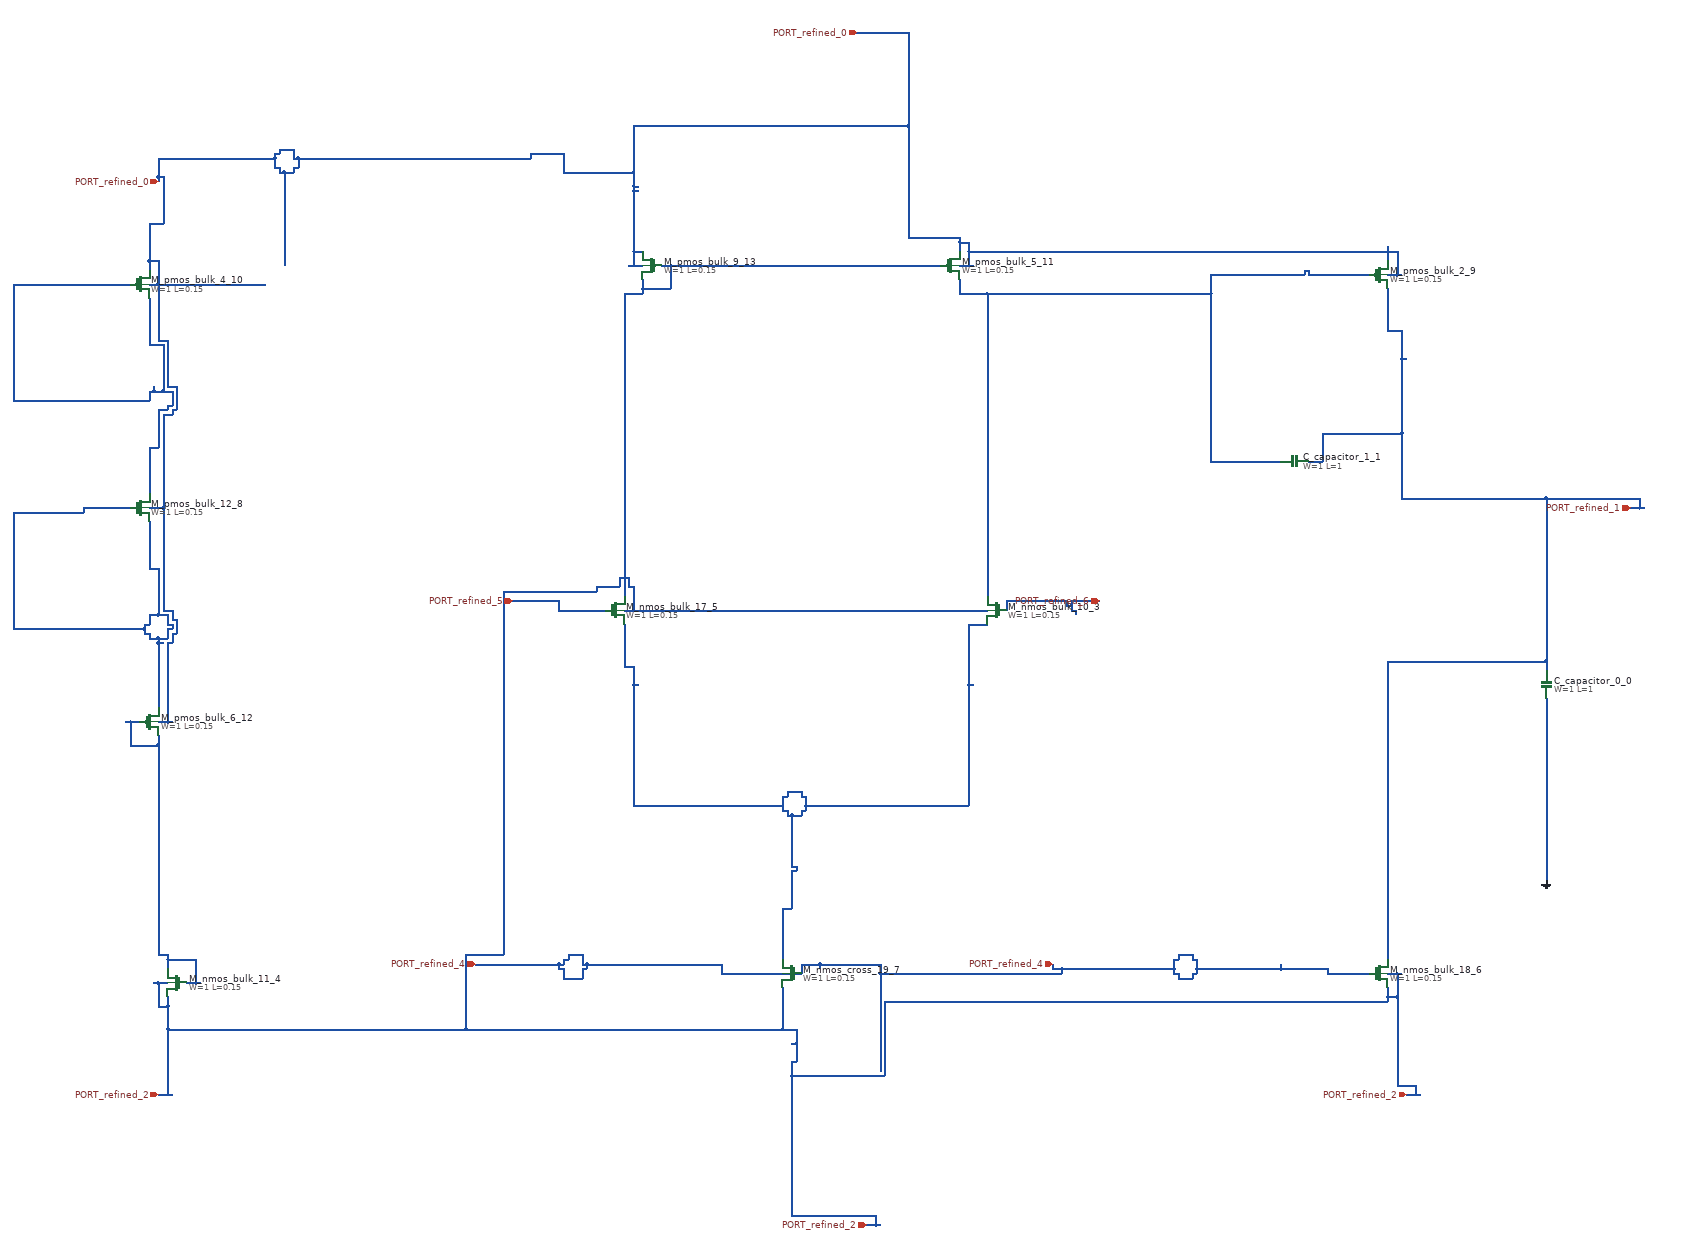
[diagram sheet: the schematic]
v {xschem version=3.4.8 file_version=1.2}
G {}
K {}
V {}
S {}
E {}
C {sky130_fd_pr/cap_mim_m3_1.sym} 3380 1500 2 0 {name="C_capacitor_0_0" model=cap_mim_m3_1 W=1 L=1 MF=1 spiceprefix=X}
C {sky130_fd_pr/cap_mim_m3_1.sym} 2840 1020 1 0 {name="C_capacitor_1_1" model=cap_mim_m3_1 W=1 L=1 MF=1 spiceprefix=X}
C {devices/gnd.sym} 3380 1920 0 0 {name="l_gnd_14_2" lab="GND"}
C {sky130_fd_pr/nfet_01v8.sym} 2200 1340 0 1 {name="M_nmos_bulk_10_3"
W=1
L=0.15
nf=1 
mult=1
ad="expr('int((@nf + 1)/2) * @W / @nf * 0.29')"
pd="expr('2*int((@nf + 1)/2) * (@W / @nf + 0.29)')"
as="expr('int((@nf + 2)/2) * @W / @nf * 0.29')"
ps="expr('2*int((@nf + 2)/2) * (@W / @nf + 0.29)')"
nrd="expr('0.29 / @W ')" nrs="expr('0.29 / @W ')"
sa=0 sb=0 sd=0
model=nfet_01v8
spiceprefix=X
}
C {sky130_fd_pr/nfet_01v8.sym} 440 2140 0 1 {name="M_nmos_bulk_11_4"
W=1
L=0.15
nf=1 
mult=1
ad="expr('int((@nf + 1)/2) * @W / @nf * 0.29')"
pd="expr('2*int((@nf + 1)/2) * (@W / @nf + 0.29)')"
as="expr('int((@nf + 2)/2) * @W / @nf * 0.29')"
ps="expr('2*int((@nf + 2)/2) * (@W / @nf + 0.29)')"
nrd="expr('0.29 / @W ')" nrs="expr('0.29 / @W ')"
sa=0 sb=0 sd=0
model=nfet_01v8
spiceprefix=X
}
C {sky130_fd_pr/nfet_01v8.sym} 1380 1340 0 0 {name="M_nmos_bulk_17_5"
W=1
L=0.15
nf=1 
mult=1
ad="expr('int((@nf + 1)/2) * @W / @nf * 0.29')"
pd="expr('2*int((@nf + 1)/2) * (@W / @nf + 0.29)')"
as="expr('int((@nf + 2)/2) * @W / @nf * 0.29')"
ps="expr('2*int((@nf + 2)/2) * (@W / @nf + 0.29)')"
nrd="expr('0.29 / @W ')" nrs="expr('0.29 / @W ')"
sa=0 sb=0 sd=0
model=nfet_01v8
spiceprefix=X
}
C {sky130_fd_pr/nfet_01v8.sym} 3020 2120 0 0 {name="M_nmos_bulk_18_6"
W=1
L=0.15
nf=1 
mult=1
ad="expr('int((@nf + 1)/2) * @W / @nf * 0.29')"
pd="expr('2*int((@nf + 1)/2) * (@W / @nf + 0.29)')"
as="expr('int((@nf + 2)/2) * @W / @nf * 0.29')"
ps="expr('2*int((@nf + 2)/2) * (@W / @nf + 0.29)')"
nrd="expr('0.29 / @W ')" nrs="expr('0.29 / @W ')"
sa=0 sb=0 sd=0
model=nfet_01v8
spiceprefix=X
}
C {sky130_fd_pr/nfet3_01v8.sym} 1760 2120 0 1 {name="M_nmos_cross_19_7"
W=1
L=0.15
body=GND
nf=1
mult=1
ad="expr('int((@nf + 1)/2) * @W / @nf * 0.29')"
pd="expr('2*int((@nf + 1)/2) * (@W / @nf + 0.29)')"
as="expr('int((@nf + 2)/2) * @W / @nf * 0.29')"
ps="expr('2*int((@nf + 2)/2) * (@W / @nf + 0.29)')"
nrd="expr('0.29 / @W ')" nrs="expr('0.29 / @W ')"
sa=0 sb=0 sd=0
model=nfet_01v8
spiceprefix=X
}
C {sky130_fd_pr/pfet_01v8.sym} 360 1120 0 0 {name="M_pmos_bulk_12_8"
W=1
L=0.15
nf=1
mult=1
ad="expr('int((@nf + 1)/2) * @W / @nf * 0.29')"
pd="expr('2*int((@nf + 1)/2) * (@W / @nf + 0.29)')"
as="expr('int((@nf + 2)/2) * @W / @nf * 0.29')"
ps="expr('2*int((@nf + 2)/2) * (@W / @nf + 0.29)')"
nrd="expr('0.29 / @W ')" nrs="expr('0.29 / @W ')"
sa=0 sb=0 sd=0
model=pfet_01v8
spiceprefix=X
}
C {sky130_fd_pr/pfet_01v8.sym} 3020 620 0 0 {name="M_pmos_bulk_2_9"
W=1
L=0.15
nf=1
mult=1
ad="expr('int((@nf + 1)/2) * @W / @nf * 0.29')"
pd="expr('2*int((@nf + 1)/2) * (@W / @nf + 0.29)')"
as="expr('int((@nf + 2)/2) * @W / @nf * 0.29')"
ps="expr('2*int((@nf + 2)/2) * (@W / @nf + 0.29)')"
nrd="expr('0.29 / @W ')" nrs="expr('0.29 / @W ')"
sa=0 sb=0 sd=0
model=pfet_01v8
spiceprefix=X
}
C {sky130_fd_pr/pfet_01v8.sym} 360 640 0 0 {name="M_pmos_bulk_4_10"
W=1
L=0.15
nf=1
mult=1
ad="expr('int((@nf + 1)/2) * @W / @nf * 0.29')"
pd="expr('2*int((@nf + 1)/2) * (@W / @nf + 0.29)')"
as="expr('int((@nf + 2)/2) * @W / @nf * 0.29')"
ps="expr('2*int((@nf + 2)/2) * (@W / @nf + 0.29)')"
nrd="expr('0.29 / @W ')" nrs="expr('0.29 / @W ')"
sa=0 sb=0 sd=0
model=pfet_01v8
spiceprefix=X
}
C {sky130_fd_pr/pfet_01v8.sym} 2100 600 0 0 {name="M_pmos_bulk_5_11"
W=1
L=0.15
nf=1
mult=1
ad="expr('int((@nf + 1)/2) * @W / @nf * 0.29')"
pd="expr('2*int((@nf + 1)/2) * (@W / @nf + 0.29)')"
as="expr('int((@nf + 2)/2) * @W / @nf * 0.29')"
ps="expr('2*int((@nf + 2)/2) * (@W / @nf + 0.29)')"
nrd="expr('0.29 / @W ')" nrs="expr('0.29 / @W ')"
sa=0 sb=0 sd=0
model=pfet_01v8
spiceprefix=X
}
C {sky130_fd_pr/pfet_01v8.sym} 380 1580 0 0 {name="M_pmos_bulk_6_12"
W=1
L=0.15
nf=1
mult=1
ad="expr('int((@nf + 1)/2) * @W / @nf * 0.29')"
pd="expr('2*int((@nf + 1)/2) * (@W / @nf + 0.29)')"
as="expr('int((@nf + 2)/2) * @W / @nf * 0.29')"
ps="expr('2*int((@nf + 2)/2) * (@W / @nf + 0.29)')"
nrd="expr('0.29 / @W ')" nrs="expr('0.29 / @W ')"
sa=0 sb=0 sd=0
model=pfet_01v8
spiceprefix=X
}
C {sky130_fd_pr/pfet_01v8.sym} 1460 600 0 1 {name="M_pmos_bulk_9_13"
W=1
L=0.15
nf=1
mult=1
ad="expr('int((@nf + 1)/2) * @W / @nf * 0.29')"
pd="expr('2*int((@nf + 1)/2) * (@W / @nf + 0.29)')"
as="expr('int((@nf + 2)/2) * @W / @nf * 0.29')"
ps="expr('2*int((@nf + 2)/2) * (@W / @nf + 0.29)')"
nrd="expr('0.29 / @W ')" nrs="expr('0.29 / @W ')"
sa=0 sb=0 sd=0
model=pfet_01v8
spiceprefix=X
}
C {devices/ipin.sym} 1920 2660 0 0 {name="p_port_13_14" lab="PORT_refined_2"}
C {devices/ipin.sym} 1900 100 0 0 {name="p_port_15_15" lab="PORT_refined_0"}
C {devices/ipin.sym} 400 420 0 0 {name="p_port_16_16" lab="PORT_refined_0"}
C {devices/ipin.sym} 2320 2100 0 0 {name="p_port_21_17" lab="PORT_refined_4"}
C {devices/ipin.sym} 400 2380 0 0 {name="p_port_22_18" lab="PORT_refined_2"}
C {devices/ipin.sym} 3080 2380 0 0 {name="p_port_23_19" lab="PORT_refined_2"}
C {devices/ipin.sym} 1080 2100 0 0 {name="p_port_24_20" lab="PORT_refined_4"}
C {devices/ipin.sym} 3560 1120 0 0 {name="p_port_3_21" lab="PORT_refined_1"}
C {devices/ipin.sym} 1160 1320 0 0 {name="p_port_7_22" lab="PORT_refined_5"}
C {devices/ipin.sym} 2420 1320 0 0 {name="p_port_8_23" lab="PORT_refined_6"}
N 400 1580 420 1580 {}
N 420 1580 430 1580 {}
N 420 1410 430 1410 {}
N 430 1390 440 1390 {}
N 430 1360 440 1360 {}
N 410 1340 430 1340 {}
N 380 1120 410 1120 {}
N 410 920 430 920 {}
N 430 910 440 910 {}
N 420 860 440 860 {}
N 400 760 420 760 {}
N 380 640 400 640 {}
N 400 640 630 640 {}
N 3040 620 3060 620 {}
N 3060 620 3070 620 {}
N 1410 600 1420 600 {}
N 1420 600 1440 600 {}
N 2120 600 2140 600 {}
N 2140 600 2150 600 {}
N 380 590 400 590 {}
N 1420 570 1440 570 {}
N 2140 570 3040 570 {}
N 3040 570 3060 570 {}
N 2120 550 2140 550 {}
N 2010 540 2120 540 {}
N 380 510 410 510 {}
N 1420 440 1430 440 {}
N 1420 430 1430 430 {}
N 400 410 410 410 {}
N 660 400 670 400 {}
N 670 400 690 400 {}
N 1270 400 1420 400 {}
N 650 390 660 390 {}
N 690 390 700 390 {}
N 400 370 650 370 {}
N 690 370 700 370 {}
N 700 370 1200 370 {}
N 650 360 660 360 {}
N 1200 360 1270 360 {}
N 660 350 690 350 {}
N 1420 300 2010 300 {}
N 1900 100 2010 100 {}
N 380 610 380 590 {}
N 380 590 380 510 {}
N 400 760 400 640 {}
N 400 640 400 590 {}
N 400 420 400 410 {}
N 400 410 400 370 {}
N 410 1340 410 1120 {}
N 410 1120 410 920 {}
N 410 510 410 410 {}
N 420 1580 420 1410 {}
N 420 860 420 760 {}
N 430 1410 430 1390 {}
N 430 1360 430 1340 {}
N 430 920 430 910 {}
N 440 1390 440 1360 {}
N 440 910 440 860 {}
N 650 390 650 370 {}
N 650 370 650 360 {}
N 660 400 660 390 {}
N 660 360 660 350 {}
N 670 600 670 400 {}
N 690 400 690 390 {}
N 690 370 690 350 {}
N 700 390 700 370 {}
N 1200 370 1200 360 {}
N 1270 400 1270 360 {}
N 1420 600 1420 570 {}
N 1420 570 1420 440 {}
N 1420 440 1420 430 {}
N 1420 430 1420 400 {}
N 1420 400 1420 300 {}
N 2010 540 2010 300 {}
N 2010 300 2010 100 {}
N 2120 570 2120 550 {}
N 2120 550 2120 540 {}
N 2140 600 2140 570 {}
N 2140 570 2140 550 {}
N 3040 590 3040 570 {}
N 3040 570 3040 560 {}
N 3060 620 3060 570 {}
N 3040 1450 3380 1450 {}
N 3560 1120 3580 1120 {}
N 3580 1120 3590 1120 {}
N 3070 1100 3380 1100 {}
N 3380 1100 3580 1100 {}
N 2870 1020 2900 1020 {}
N 2900 960 3070 960 {}
N 3070 800 3080 800 {}
N 3040 740 3070 740 {}
N 2900 1020 2900 960 {}
N 3040 2090 3040 1450 {}
N 3040 740 3040 650 {}
N 3070 1100 3070 960 {}
N 3070 960 3070 800 {}
N 3070 800 3070 740 {}
N 3380 1470 3380 1450 {}
N 3380 1450 3380 1100 {}
N 3580 1120 3580 1100 {}
N 380 990 400 990 {}
N 400 910 420 910 {}
N 420 900 430 900 {}
N 90 890 380 890 {}
N 380 870 390 870 {}
N 390 870 410 870 {}
N 410 870 430 870 {}
N 380 770 410 770 {}
N 90 640 340 640 {}
N 90 890 90 640 {}
N 380 1090 380 990 {}
N 380 890 380 870 {}
N 380 770 380 670 {}
N 390 870 390 860 {}
N 400 990 400 910 {}
N 410 870 410 770 {}
N 420 910 420 900 {}
N 430 900 430 870 {}
N 400 1410 410 1410 {}
N 380 1400 400 1400 {}
N 400 1400 420 1400 {}
N 370 1390 380 1390 {}
N 90 1380 370 1380 {}
N 420 1380 430 1380 {}
N 370 1370 380 1370 {}
N 420 1370 430 1370 {}
N 380 1350 400 1350 {}
N 400 1350 420 1350 {}
N 380 1250 400 1250 {}
N 90 1130 240 1130 {}
N 240 1120 340 1120 {}
N 90 1380 90 1130 {}
N 240 1130 240 1120 {}
N 370 1390 370 1380 {}
N 370 1380 370 1370 {}
N 380 1400 380 1390 {}
N 380 1370 380 1350 {}
N 380 1250 380 1150 {}
N 400 1550 400 1410 {}
N 400 1410 400 1400 {}
N 400 1350 400 1250 {}
N 420 1400 420 1380 {}
N 420 1370 420 1350 {}
N 430 1380 430 1370 {}
N 460 2140 480 2140 {}
N 480 2140 490 2140 {}
N 420 2090 480 2090 {}
N 400 2080 420 2080 {}
N 340 1630 400 1630 {}
N 330 1580 340 1580 {}
N 340 1580 360 1580 {}
N 340 1630 340 1580 {}
N 400 2080 400 1630 {}
N 400 1630 400 1610 {}
N 420 2110 420 2090 {}
N 420 2090 420 2080 {}
N 480 2140 480 2090 {}
N 1920 2660 1940 2660 {}
N 1940 2660 1950 2660 {}
N 1760 2640 1940 2640 {}
N 400 2380 420 2380 {}
N 420 2380 430 2380 {}
N 3080 2380 3100 2380 {}
N 3100 2380 3110 2380 {}
N 3060 2360 3100 2360 {}
N 1760 2340 1960 2340 {}
N 1760 2310 1770 2310 {}
N 1760 2270 1770 2270 {}
N 420 2240 1060 2240 {}
N 1060 2240 1740 2240 {}
N 1740 2240 1770 2240 {}
N 400 2190 420 2190 {}
N 1960 2180 3040 2180 {}
N 3040 2170 3060 2170 {}
N 390 2140 400 2140 {}
N 400 2140 420 2140 {}
N 3040 2120 3060 2120 {}
N 3060 2120 3070 2120 {}
N 1060 2080 1140 2080 {}
N 1400 1340 1420 1340 {}
N 1420 1340 2180 1340 {}
N 1140 1300 1340 1300 {}
N 1340 1290 1390 1290 {}
N 1410 1290 1420 1290 {}
N 1390 1270 1410 1270 {}
N 400 2190 400 2140 {}
N 420 2380 420 2240 {}
N 420 2240 420 2190 {}
N 420 2190 420 2170 {}
N 1060 2240 1060 2080 {}
N 1140 2080 1140 1300 {}
N 1340 1300 1340 1290 {}
N 1390 1290 1390 1270 {}
N 1410 1290 1410 1270 {}
N 1420 1340 1420 1290 {}
N 1740 2240 1740 2150 {}
N 1760 2640 1760 2340 {}
N 1760 2340 1760 2310 {}
N 1770 2310 1770 2270 {}
N 1770 2270 1770 2240 {}
N 1940 2660 1940 2640 {}
N 1960 2340 1960 2180 {}
N 3040 2180 3040 2170 {}
N 3040 2170 3040 2150 {}
N 3060 2360 3060 2170 {}
N 3060 2170 3060 2120 {}
N 3100 2380 3100 2360 {}
N 3380 1920 3380 1530 {}
N 1270 2130 1310 2130 {}
N 2590 2130 2620 2130 {}
N 1610 2120 1780 2120 {}
N 1950 2120 2340 2120 {}
N 2580 2120 2590 2120 {}
N 2620 2120 2630 2120 {}
N 2910 2120 3000 2120 {}
N 1260 2110 1270 2110 {}
N 1310 2110 1320 2110 {}
N 2320 2110 2340 2110 {}
N 2340 2110 2580 2110 {}
N 2630 2110 2810 2110 {}
N 2810 2110 2910 2110 {}
N 1080 2100 1260 2100 {}
N 1260 2100 1270 2100 {}
N 1310 2100 1320 2100 {}
N 1320 2100 1610 2100 {}
N 1780 2100 1820 2100 {}
N 1820 2100 1950 2100 {}
N 1270 2090 1280 2090 {}
N 2580 2090 2590 2090 {}
N 2620 2090 2630 2090 {}
N 1280 2080 1310 2080 {}
N 2590 2080 2620 2080 {}
N 1260 2110 1260 2100 {}
N 1270 2130 1270 2110 {}
N 1270 2100 1270 2090 {}
N 1280 2090 1280 2080 {}
N 1310 2130 1310 2110 {}
N 1310 2100 1310 2080 {}
N 1320 2110 1320 2100 {}
N 1610 2120 1610 2100 {}
N 1780 2120 1780 2100 {}
N 1820 2110 1820 2100 {}
N 1950 2330 1950 2120 {}
N 1950 2120 1950 2100 {}
N 2320 2110 2320 2100 {}
N 2340 2120 2340 2110 {}
N 2580 2120 2580 2110 {}
N 2580 2110 2580 2090 {}
N 2590 2130 2590 2120 {}
N 2590 2090 2590 2080 {}
N 2620 2130 2620 2120 {}
N 2620 2090 2620 2080 {}
N 2630 2120 2630 2110 {}
N 2630 2110 2630 2090 {}
N 2810 2110 2810 2100 {}
N 2910 2120 2910 2110 {}
N 1260 1340 1360 1340 {}
N 1160 1320 1260 1320 {}
N 1260 1340 1260 1320 {}
N 2360 1340 2370 1340 {}
N 2350 1330 2360 1330 {}
N 2220 1320 2350 1320 {}
N 2360 1320 2420 1320 {}
N 2220 1340 2220 1320 {}
N 2350 1330 2350 1320 {}
N 2360 1340 2360 1330 {}
N 2360 1330 2360 1320 {}
N 2370 1350 2370 1340 {}
N 1400 660 1440 660 {}
N 1440 650 1500 650 {}
N 1480 600 1500 600 {}
N 1500 600 2080 600 {}
N 1400 1310 1400 660 {}
N 1440 660 1440 650 {}
N 1440 650 1440 630 {}
N 1500 650 1500 600 {}
N 2660 1020 2810 1020 {}
N 2120 660 2180 660 {}
N 2180 660 2660 660 {}
N 2660 620 2860 620 {}
N 2870 620 3000 620 {}
N 2860 610 2870 610 {}
N 2120 660 2120 630 {}
N 2180 1310 2180 660 {}
N 2660 1020 2660 660 {}
N 2660 660 2660 620 {}
N 2860 620 2860 610 {}
N 2870 620 2870 610 {}
N 1740 1980 1760 1980 {}
N 1760 1900 1770 1900 {}
N 1760 1890 1770 1890 {}
N 1750 1780 1760 1780 {}
N 1760 1780 1780 1780 {}
N 1740 1770 1750 1770 {}
N 1780 1770 1790 1770 {}
N 1420 1760 1740 1760 {}
N 1790 1760 2140 1760 {}
N 1740 1740 1750 1740 {}
N 1780 1740 1790 1740 {}
N 1750 1730 1780 1730 {}
N 1420 1500 1430 1500 {}
N 2140 1500 2150 1500 {}
N 1400 1460 1420 1460 {}
N 2140 1370 2180 1370 {}
N 1400 1460 1400 1370 {}
N 1420 1760 1420 1500 {}
N 1420 1500 1420 1460 {}
N 1740 2090 1740 1980 {}
N 1740 1770 1740 1760 {}
N 1740 1760 1740 1740 {}
N 1750 1780 1750 1770 {}
N 1750 1740 1750 1730 {}
N 1760 1980 1760 1900 {}
N 1760 1890 1760 1780 {}
N 1770 1900 1770 1890 {}
N 1780 1780 1780 1770 {}
N 1780 1740 1780 1730 {}
N 1790 1770 1790 1760 {}
N 1790 1760 1790 1740 {}
N 2140 1760 2140 1500 {}
N 2140 1500 2140 1370 {}
